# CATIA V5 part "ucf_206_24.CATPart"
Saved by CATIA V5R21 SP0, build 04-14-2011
Part number: ucf_206_24
Bounding box of the stored display mesh (mm): x -12.243 to -5.227, y -19.6 to -13.6, z 12.546 to 19.716
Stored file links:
  C:\TPO v2\SharedFS\Outgoing\ucf_206_24.CATPart

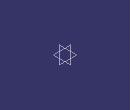
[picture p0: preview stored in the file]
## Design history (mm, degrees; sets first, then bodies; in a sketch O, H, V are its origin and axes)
AxisSystem1: origin (0, 0, 0), X (1, 0, 0), Y (0, 1, 0), Z (0, 0, 1)
Body1 "ucf_206_24" (main body)
  Solid1: solid without history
